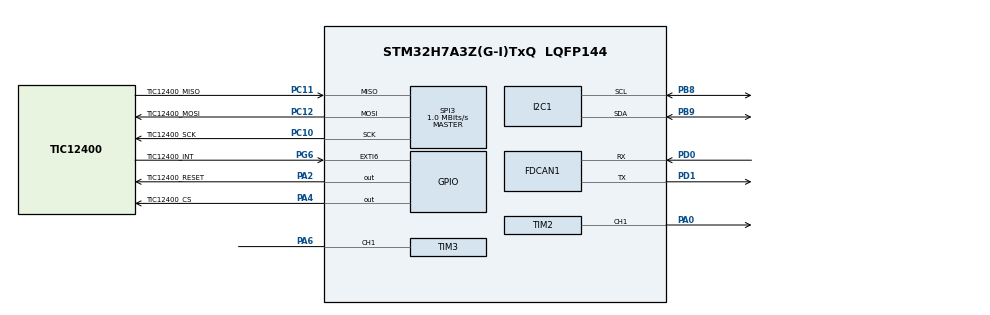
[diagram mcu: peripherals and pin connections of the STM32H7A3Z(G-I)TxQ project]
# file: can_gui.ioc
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CORTEX_M7.default_mode_Activation=1
FDCAN1.AutoRetransmission=ENABLE
FDCAN1.CalculateBaudRateNominal=500000
FDCAN1.CalculateTimeBitNominal=2000
FDCAN1.CalculateTimeQuantumNominal=125.0
FDCAN1.ExtFiltersNbr=1
FDCAN1.NominalPrescaler=4
FDCAN1.NominalSyncJumpWidth=4
FDCAN1.NominalTimeSeg1=12
FDCAN1.NominalTimeSeg2=3
FDCAN1.RxFifo0ElmtsNbr=32
FDCAN1.StdFiltersNbr=1
FDCAN1.TxFifoQueueElmtsNbr=3
IWDG1.Prescaler=IWDG_PRESCALER_128
IWDG1.Reload=999
IWDG1.Window=4095
Mcu.Family=STM32H7
Mcu.Name=STM32H7A3Z(G-I)TxQ
Mcu.Package=LQFP144
NUCLEO-H7A3ZI-Q.BUTTON=1
NUCLEO-H7A3ZI-Q.LD1=true
NUCLEO-H7A3ZI-Q.LD2=true
NUCLEO-H7A3ZI-Q.LD3=true
NUCLEO-H7A3ZI-Q.VCP=true
NVIC.EXTI15_10_IRQn=true\:15\:0\:false\:false\:true\:false\:true\:true
NVIC.EXTI9_5_IRQn=true\:3\:0\:false\:false\:true\:true\:true\:true
NVIC.FDCAN1_IT0_IRQn=true\:2\:0\:false\:false\:true\:true\:true\:true
NVIC.PriorityGroup=NVIC_PRIORITYGROUP_4
PA0.Signal=S_TIM2_CH1_ETR
PA2.GPIO_Label=TIC12400_RESET
PA2.GPIO_ModeDefaultOutputPP=GPIO_MODE_OUTPUT_PP
PA2.GPIO_PuPd=GPIO_NOPULL
PA2.GPIO_Speed=GPIO_SPEED_FREQ_LOW
PA2.PinState=GPIO_PIN_RESET
PA2.Signal=GPIO_Output
PA4.GPIO_Label=TIC12400_CS
PA4.GPIO_ModeDefaultOutputPP=GPIO_MODE_OUTPUT_PP
PA4.GPIO_PuPd=GPIO_NOPULL
PA4.GPIO_Speed=GPIO_SPEED_FREQ_LOW
PA4.PinState=GPIO_PIN_SET
PA4.Signal=GPIO_Output
PA6.Signal=S_TIM3_CH1
PB8.GPIO_Pu=GPIO_PULLUP
PB8.Mode=I2C
PB8.Signal=I2C1_SCL
PB9.GPIO_Pu=GPIO_PULLUP
PB9.Mode=I2C
PB9.Signal=I2C1_SDA
PC10.GPIO_Label=TIC12400_SCK
PC10.GPIO_Speed=GPIO_SPEED_FREQ_HIGH
PC10.Mode=Full_Duplex_Master
PC10.Signal=SPI3_SCK
PC11.GPIO_Label=TIC12400_MISO
PC11.GPIO_Speed=GPIO_SPEED_FREQ_HIGH
PC11.Mode=Full_Duplex_Master
PC11.Signal=SPI3_MISO
PC12.GPIO_Label=TIC12400_MOSI
PC12.GPIO_Speed=GPIO_SPEED_FREQ_HIGH
PC12.Mode=Full_Duplex_Master
PC12.Signal=SPI3_MOSI
PC14-OSC32_IN.GPIO_Label=OSC32_IN
PC14-OSC32_IN.Signal=RCC_OSC32_IN
PC15-OSC32_OUT.GPIO_Label=OSC32_OUT
PC15-OSC32_OUT.Signal=RCC_OSC32_OUT
PD0.Mode=FDCAN_Activate
PD0.Signal=FDCAN1_RX
PD1.Mode=FDCAN_Activate
PD1.Signal=FDCAN1_TX
PD8.Signal=USART3_TX
PD9.Signal=USART3_RX
PG6.GPIO_Label=TIC12400_INT
PG6.GPIO_ModeDefaultEXTI=GPIO_MODE_IT_FALLING
PG6.GPIO_PuPd=GPIO_NOPULL
PG6.Signal=GPXTI6
PH0-OSC_IN.GPIO_Label=PH0-MCU
PH0-OSC_IN.Signal=RCC_OSC_IN
PH1-OSC_OUT.GPIO_Label=PH1-MCU
PH1-OSC_OUT.Signal=RCC_OSC_OUT
ProjectManager.HeapSize=0x200
ProjectManager.StackSize=0x800
ProjectManager.TargetToolchain=STM32CubeIDE
RCC.ADCFreq_Value=129000000
RCC.APB1Freq_Value=64000000
RCC.APB2Freq_Value=64000000
RCC.APB3Freq_Value=64000000
RCC.APB4Freq_Value=64000000
RCC.CortexFreq_Value=64000000
RCC.DIVM1=3
RCC.DIVM3=1
RCC.DIVN1=96
RCC.DIVP1=4
RCC.DIVN3=24
RCC.DIVQ1=8
RCC.DIVR1=4
RCC.HCLKFreq_Value=64000000
RCC.HSE_VALUE=8000000
RCC.PLLFRACN=0
RCC.PLLSourceVirtual=RCC_PLLSOURCE_HSE
RCC.PWR_Regulator_Voltage_Scale=PWR_REGULATOR_VOLTAGE_SCALE0
RCC.SYSCLKFreq_VALUE=64000000
RCC.SYSCLKSource=RCC_SYSCLKSOURCE_PLLCLK
RCC.SupplySource=PWR_DIRECT_SMPS_SUPPLY
RCC.USBCLockSelection=RCC_USBCLKSOURCE_HSI48
RCC.USBFreq_Value=48000000
SH.S_TIM2_CH1_ETR.0=TIM2_CH1,PWM Generation1 CH1
SH.S_TIM3_CH1.0=TIM3_CH1,PWM Input on CH1
SPI3.BaudRatePrescaler=SPI_BAUDRATEPRESCALER_32
SPI3.CLKPhase=SPI_PHASE_2EDGE
SPI3.CLKPolarity=SPI_POLARITY_LOW
SPI3.CRCCalculation=SPI_CRCCALCULATION_DISABLE
SPI3.CalculateBaudRate=1.0 MBits/s
SPI3.DataSize=SPI_DATASIZE_8BIT
SPI3.Direction=SPI_DIRECTION_2LINES
SPI3.FirstBit=SPI_FIRSTBIT_MSB
SPI3.MasterKeepIOState=SPI_MASTER_KEEP_IO_STATE_ENABLE
SPI3.Mode=SPI_MODE_MASTER
SPI3.NSSPMode=SPI_NSS_PULSE_DISABLE
SPI3.VirtualNSS=VM_NSSSOFT
SPI3.VirtualType=VM_MASTER
TIM2.AutoReloadPreload=TIM_AUTORELOAD_PRELOAD_ENABLE
TIM2.Channel-PWM\ Generation1\ CH1=TIM_CHANNEL_1
TIM2.Period=999
TIM2.Prescaler=63
TIM2.Pulse-PWM\ Generation1\ CH1=500
TIM3.Channel-PWM\ Input\ on\ CH1=TIM_CHANNEL_1
TIM3.Period=65535
TIM3.Prescaler=63
VP_IWDG1_VS_IWDG.Mode=IWDG_Activate
VP_MEMORYMAP_VS_MEMORYMAP.Mode=CurAppReg
VP_NUCLEO-H7A3ZI-Q_VS_BSP_COMMON.Mode=COMMON
VP_TIM2_VS_ClockSourceINT.Mode=Internal
VP_TIM3_VS_ClockSourceINT.Mode=Internal
board=NUCLEO-H7A3ZI-Q

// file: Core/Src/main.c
/* USER CODE BEGIN Header */
/**
  ******************************************************************************
  * @file           : main.c
  * @brief          : Main program body
  ******************************************************************************
  * @attention
  *
  * Copyright (c) 2026 STMicroelectronics.
  * All rights reserved.
  *
  * This software is licensed under terms that can be found in the LICENSE file
  * in the root directory of this software component.
  * If no LICENSE file comes with this software, it is provided AS-IS.
  *
  ******************************************************************************
  */
/* USER CODE END Header */
#include "main.h"

/* USER CODE BEGIN Includes */
#include "can_app.h"
#include "app_control.h"
#include "app_fault.h"
#include "app_irq_policy.h"
#include "app_safe_state.h"
#include "app_startup.h"
#include "app_timing.h"
#include "rtc_app.h"
#include "app_log.h"
#include "app_reset_reason.h"
#include "app_watchdog.h"
#include "app_watchdog_evidence.h"
#include "pwm_control.h"
#include "input_capture.h"
#include "pwm_self_test.h"
#include "tic12400_probe.h"
#include "tic12400_can.h"

/* USER CODE END Includes */

/* USER CODE BEGIN PD */
#define APP_PLL_M                         3UL
#define APP_PLL_N                         96UL
#define APP_PLL_P                         4UL
#define APP_PLL_Q                         8UL
#define APP_PLL_R                         4UL
#define APP_FDCAN_NOMINAL_PRESCALER       4UL
#define APP_FDCAN_NOMINAL_TIME_SEG1       12UL
#define APP_FDCAN_NOMINAL_TIME_SEG2       3UL
#define APP_FDCAN_NOMINAL_TQ_COUNT        \
  (1UL + APP_FDCAN_NOMINAL_TIME_SEG1 + APP_FDCAN_NOMINAL_TIME_SEG2)
#define APP_PLL_VCO_HZ                    \
  ((HSE_VALUE * APP_PLL_N) / APP_PLL_M)
#define APP_SYSCLK_HZ                     (APP_PLL_VCO_HZ / APP_PLL_P)
#define APP_FDCAN_KERNEL_CLOCK_HZ         (APP_PLL_VCO_HZ / APP_PLL_Q)
#define APP_FDCAN_NOMINAL_BITRATE_HZ      \
  (APP_FDCAN_KERNEL_CLOCK_HZ / APP_FDCAN_NOMINAL_PRESCALER / \
   APP_FDCAN_NOMINAL_TQ_COUNT)
#define APP_FDCAN_MESSAGE_RAM_WORDS        \
  (1UL + 2UL + (CAN_APP_RX_FIFO0_ELEMENTS * 4UL) + (3UL * 4UL))

_Static_assert(HSE_VALUE == 8000000UL,
               "Board clock tree requires the 8 MHz ST-LINK MCO");
_Static_assert(APP_PLL_VCO_HZ == 256000000UL,
               "PLL VCO clock changed");
_Static_assert(APP_SYSCLK_HZ == 64000000UL,
               "System clock changed");
_Static_assert(APP_FDCAN_KERNEL_CLOCK_HZ == 32000000UL,
               "FDCAN kernel clock changed");
_Static_assert(APP_FDCAN_NOMINAL_BITRATE_HZ == 500000UL,
               "FDCAN nominal bitrate changed");
_Static_assert(CAN_APP_RX_FIFO0_ELEMENTS <= 64U,
               "FDCAN RX FIFO0 exceeds the hardware limit");
_Static_assert(CAN_APP_RX_FIFO0_WATERMARK < CAN_APP_RX_FIFO0_ELEMENTS,
               "FDCAN RX FIFO0 watermark must leave burst headroom");
_Static_assert(APP_FDCAN_MESSAGE_RAM_WORDS <= 2560UL,
               "FDCAN message RAM allocation exceeds SRAMCAN");
_Static_assert(__NVIC_PRIO_BITS == 4U,
               "IRQ policy requires 16 Cortex-M7 priority levels");
_Static_assert(TICK_INT_PRIORITY == APP_IRQ_PRIORITY_SYSTICK,
               "HAL tick priority diverges from the IRQ policy");
_Static_assert(BSP_BUTTON_USER_IT_PRIORITY ==
               APP_IRQ_PRIORITY_USER_BUTTON,
               "BSP button priority diverges from the IRQ policy");
/* USER CODE END PD */

COM_InitTypeDef BspCOMInit;

FDCAN_HandleTypeDef hfdcan1;

I2C_HandleTypeDef hi2c1;

IWDG_HandleTypeDef hiwdg1;

SPI_HandleTypeDef hspi3;

TIM_HandleTypeDef htim2;
TIM_HandleTypeDef htim3;

/* USER CODE BEGIN PV */
volatile uint8_t g_fdcan1_msp_ready;
volatile uint8_t g_i2c1_msp_ready;
volatile uint8_t g_spi3_msp_ready;
/* USER CODE END PV */

void SystemClock_Config(void);
static void MPU_Config(void);
static void MX_GPIO_Init(void);
static App_Startup_Result_t MX_FDCAN1_Init(void);
static App_Startup_Result_t MX_I2C1_Init(void);
static App_Startup_Result_t MX_SPI3_Init(void);
static void MX_IWDG1_Init(void);
static App_Startup_Result_t MX_TIM2_Init(void);
static App_Startup_Result_t MX_TIM3_Init(void);

int main(void)
{

  /* USER CODE BEGIN 1 */
  App_Startup_Result_t init_result;
  uint32_t loop_timing_start;
  uint32_t service_timing_start;

  /* USER CODE END 1 */

  /* MPU Configuration--------------------------------------------------------*/
  MPU_Config();

  /* MCU Configuration--------------------------------------------------------*/

  /* Reset of all peripherals, Initializes the Flash interface and the Systick. */
  HAL_Init();

  /* USER CODE BEGIN Init */

  App_ResetReason_Capture();
  App_Fault_CaptureBoot();
  App_Watchdog_Evidence_CaptureBoot(App_ResetReason_WasIwdgReset());

  /* USER CODE END Init */

  /* Configure the system clock */
  SystemClock_Config();

  /* USER CODE BEGIN SysInit */

  App_Timing_Init(SystemCoreClock);

  /* USER CODE END SysInit */

  /* Initialize all configured peripherals */
  MX_GPIO_Init();
  App_SafeState_Engage();
  App_Startup_Init(APP_STARTUP_EXPECTED_RESOURCES);

  /* IWDG is mandatory and starts before non-critical peripherals. */
  MX_IWDG1_Init();
  if (App_Watchdog_Init(&hiwdg1) != HAL_OK)
  {
    Error_Handler();
  }

  init_result = MX_FDCAN1_Init();
  App_Startup_Record(APP_STARTUP_RESOURCE_FDCAN, init_result);
  init_result = MX_I2C1_Init();
  App_Startup_Record(APP_STARTUP_RESOURCE_I2C, init_result);
  init_result = MX_SPI3_Init();
  App_Startup_Record(APP_STARTUP_RESOURCE_SPI, init_result);
  init_result = MX_TIM2_Init();
  App_Startup_Record(APP_STARTUP_RESOURCE_PWM_TIMER, init_result);
  if (init_result != APP_STARTUP_RESULT_OK)
  {
    App_SafeState_Engage();
  }
  init_result = MX_TIM3_Init();
  App_Startup_Record(APP_STARTUP_RESOURCE_CAPTURE_TIMER, init_result);
  /* USER CODE BEGIN 2 */
  App_Log_Init();
  App_Fault_Snapshot_t fault_snapshot;
  App_Fault_GetSnapshot(&fault_snapshot);
  if (fault_snapshot.valid != 0U)
  {
    (void)App_Log_Push(APP_LOG_SOURCE_SYSTEM,
                       APP_LOG_SEVERITY_FAULT,
                       APP_LOG_EVENT_CPU_FAULT,
                       fault_snapshot.type,
                       fault_snapshot.pc);
    (void)App_Log_Push(APP_LOG_SOURCE_SYSTEM,
                       APP_LOG_SEVERITY_FAULT,
                       APP_LOG_EVENT_CPU_FAULT_STATUS,
                       fault_snapshot.cfsr,
                       fault_snapshot.hfsr);
  }
  if (App_Startup_IsReady(APP_STARTUP_RESOURCE_PWM_TIMER) != 0U)
  {
    init_result =
        (PWM_Control_Init(&htim2,
                          TIM_CHANNEL_1,
                          1000000UL) == PWM_CONTROL_OK)
        ? APP_STARTUP_RESULT_OK
        : APP_STARTUP_RESULT_PWM_CONTROL_INIT;
  }
  else
  {
    init_result = APP_STARTUP_RESULT_PWM_CONTROL_INIT;
  }
  App_Startup_Record(APP_STARTUP_RESOURCE_PWM_CONTROL, init_result);

  if ((init_result == APP_STARTUP_RESULT_OK) &&
      (PWM_Control_Set(10000U, 90U) != PWM_CONTROL_OK))
  {
    init_result = APP_STARTUP_RESULT_PWM_CONTROL_DEFAULT;
    App_Startup_Record(APP_STARTUP_RESOURCE_PWM_CONTROL, init_result);
    App_SafeState_Engage();
  }

  if (App_Startup_IsReady(APP_STARTUP_RESOURCE_CAPTURE_TIMER) != 0U)
  {
    init_result =
        (Input_Capture_Init(&htim3, 1000000UL) == INPUT_CAPTURE_OK)
        ? APP_STARTUP_RESULT_OK
        : APP_STARTUP_RESULT_INPUT_CAPTURE_INIT;
  }
  else
  {
    init_result = APP_STARTUP_RESULT_INPUT_CAPTURE_INIT;
  }
  App_Startup_Record(APP_STARTUP_RESOURCE_INPUT_CAPTURE, init_result);

  TIC12400_Probe_Init(
      &hspi3,
      App_Startup_IsReady(APP_STARTUP_RESOURCE_SPI));
  PWM_SelfTest_Init();
  App_Control_Init();
  App_ResetReason_Snapshot_t reset_reason;
  App_ResetReason_GetSnapshot(&reset_reason);
  (void)App_Log_Push(APP_LOG_SOURCE_SYSTEM,
                     APP_LOG_SEVERITY_INFO,
                     APP_LOG_EVENT_SYSTEM_BOOT,
                     reset_reason.decoded_flags,
                     reset_reason.raw_rsr);

  App_Watchdog_ResetEvidence_t watchdog_evidence;
  App_Watchdog_Evidence_Get(&watchdog_evidence);
  if (watchdog_evidence.valid != 0U)
  {
    (void)App_Log_Push(APP_LOG_SOURCE_SYSTEM,
                       APP_LOG_SEVERITY_FAULT,
                       APP_LOG_EVENT_WATCHDOG_RESET_EVIDENCE,
                       watchdog_evidence.cause,
                       watchdog_evidence.missing_heartbeat_mask);
  }

  (void)CAN_App_Init(
      App_Startup_IsReady(APP_STARTUP_RESOURCE_FDCAN));
  TIC12400_CAN_Init();
  PCA2131_Init_Check(
      App_Startup_IsReady(APP_STARTUP_RESOURCE_I2C));
  if (CAN_App_IsAvailable() != 0U)
  {
    CAN_Send_System_Status();
  }

  /* USER CODE END 2 */

  /* Initialize leds */
  BSP_LED_Init(LED_GREEN);
  BSP_LED_Init(LED_YELLOW);
  BSP_LED_Init(LED_RED);
  if (CAN_App_IsAvailable() == 0U)
  {
    BSP_LED_On(LED_YELLOW);
  }

  /* Initialize USER push-button, will be used to trigger an interrupt each time it's pressed.*/
  BSP_PB_Init(BUTTON_USER, BUTTON_MODE_EXTI);

  /* Initialize COM1 port (115200, 8 bits (7-bit data + 1 stop bit), no parity */
  BspCOMInit.BaudRate   = 115200;
  BspCOMInit.WordLength = COM_WORDLENGTH_8B;
  BspCOMInit.StopBits   = COM_STOPBITS_1;
  BspCOMInit.Parity     = COM_PARITY_NONE;
  BspCOMInit.HwFlowCtl  = COM_HWCONTROL_NONE;
  if (BSP_COM_Init(COM1, &BspCOMInit) != BSP_ERROR_NONE)
  {
    App_Startup_Record(APP_STARTUP_RESOURCE_COM,
                       APP_STARTUP_RESULT_COM_INIT);
  }
  else
  {
    App_Startup_Record(APP_STARTUP_RESOURCE_COM,
                       APP_STARTUP_RESULT_OK);
  }

  App_Startup_Snapshot_t startup_snapshot;
  App_Startup_GetSnapshot(&startup_snapshot);
  if (startup_snapshot.degraded != 0U)
  {
    BSP_LED_On(LED_YELLOW);
    (void)App_Log_Push(APP_LOG_SOURCE_SYSTEM,
                       APP_LOG_SEVERITY_FAULT,
                       APP_LOG_EVENT_STARTUP_DEGRADED,
                       startup_snapshot.failed_mask,
                       startup_snapshot.first_failure_result);
  }

  /* Infinite loop */
  /* USER CODE BEGIN WHILE */
  while (1)
  {

    loop_timing_start = App_Timing_Begin();

    /* USER CODE END WHILE */

    /* USER CODE BEGIN 3 */

	  service_timing_start = App_Timing_Begin();
	  TIC12400_Probe_Process();
	  App_Timing_End(APP_TIMING_SERVICE_TIC12400_PROBE,
	                 service_timing_start);

	  service_timing_start = App_Timing_Begin();
	  App_Control_Process();
	  App_Timing_End(APP_TIMING_SERVICE_CONTROL, service_timing_start);

	  service_timing_start = App_Timing_Begin();
	  RTC_Process();
	  App_Watchdog_CheckIn(APP_WATCHDOG_HEARTBEAT_RTC_SERVICE);
	  App_Timing_End(APP_TIMING_SERVICE_RTC, service_timing_start);

	  service_timing_start = App_Timing_Begin();
	  Input_Capture_Process();
	  App_Timing_End(APP_TIMING_SERVICE_INPUT_CAPTURE,
	                 service_timing_start);

	  service_timing_start = App_Timing_Begin();
	  CAN_App_Process();
	  App_Timing_End(APP_TIMING_SERVICE_CAN_APP, service_timing_start);

	  service_timing_start = App_Timing_Begin();
	  TIC12400_CAN_Process();
	  App_Timing_End(APP_TIMING_SERVICE_TIC12400_CAN,
	                 service_timing_start);

	  service_timing_start = App_Timing_Begin();
	  App_Watchdog_CheckIn(APP_WATCHDOG_HEARTBEAT_MAIN_LOOP);
	  App_Watchdog_Process();
	  App_Timing_End(APP_TIMING_SERVICE_WATCHDOG,
	                 service_timing_start);

	  App_Timing_End(APP_TIMING_SERVICE_MAIN_LOOP, loop_timing_start);

  }
  /* USER CODE END 3 */
}

void SystemClock_Config(void)
{
  RCC_OscInitTypeDef RCC_OscInitStruct = {0};
  RCC_ClkInitTypeDef RCC_ClkInitStruct = {0};

  /*AXI clock gating */
  RCC->CKGAENR = 0xE003FFFF;

  /** Supply configuration update enable
  */
  HAL_PWREx_ConfigSupply(PWR_DIRECT_SMPS_SUPPLY);

  /** Configure the main internal regulator output voltage
  */
  __HAL_PWR_VOLTAGESCALING_CONFIG(PWR_REGULATOR_VOLTAGE_SCALE0);

  while(!__HAL_PWR_GET_FLAG(PWR_FLAG_VOSRDY)) {}

  /** Initializes the RCC Oscillators according to the specified parameters
  * in the RCC_OscInitTypeDef structure.
  */
  RCC_OscInitStruct.OscillatorType = RCC_OSCILLATORTYPE_HSE
                                   | RCC_OSCILLATORTYPE_HSI
                                   | RCC_OSCILLATORTYPE_LSI;
  RCC_OscInitStruct.HSEState = RCC_HSE_BYPASS;
  RCC_OscInitStruct.HSIState = RCC_HSI_DIV1;
  RCC_OscInitStruct.HSICalibrationValue = 64;
  RCC_OscInitStruct.LSIState = RCC_LSI_ON;
  RCC_OscInitStruct.PLL.PLLState = RCC_PLL_ON;
  RCC_OscInitStruct.PLL.PLLSource = RCC_PLLSOURCE_HSE;
  RCC_OscInitStruct.PLL.PLLM = APP_PLL_M;
  RCC_OscInitStruct.PLL.PLLN = APP_PLL_N;
  RCC_OscInitStruct.PLL.PLLP = APP_PLL_P;
  RCC_OscInitStruct.PLL.PLLQ = APP_PLL_Q;
  RCC_OscInitStruct.PLL.PLLR = APP_PLL_R;
  RCC_OscInitStruct.PLL.PLLRGE = RCC_PLL1VCIRANGE_1;
  RCC_OscInitStruct.PLL.PLLVCOSEL = RCC_PLL1VCOWIDE;
  RCC_OscInitStruct.PLL.PLLFRACN = 0;
  if (HAL_RCC_OscConfig(&RCC_OscInitStruct) != HAL_OK)
  {
    Error_Handler();
  }

  /** Initializes the CPU, AHB and APB buses clocks
  */
  RCC_ClkInitStruct.ClockType = RCC_CLOCKTYPE_HCLK|RCC_CLOCKTYPE_SYSCLK
                              |RCC_CLOCKTYPE_PCLK1|RCC_CLOCKTYPE_PCLK2
                              |RCC_CLOCKTYPE_D3PCLK1|RCC_CLOCKTYPE_D1PCLK1;
  RCC_ClkInitStruct.SYSCLKSource = RCC_SYSCLKSOURCE_PLLCLK;
  RCC_ClkInitStruct.SYSCLKDivider = RCC_SYSCLK_DIV1;
  RCC_ClkInitStruct.AHBCLKDivider = RCC_HCLK_DIV1;
  RCC_ClkInitStruct.APB3CLKDivider = RCC_APB3_DIV1;
  RCC_ClkInitStruct.APB1CLKDivider = RCC_APB1_DIV1;
  RCC_ClkInitStruct.APB2CLKDivider = RCC_APB2_DIV1;
  RCC_ClkInitStruct.APB4CLKDivider = RCC_APB4_DIV1;

  if (HAL_RCC_ClockConfig(&RCC_ClkInitStruct, FLASH_LATENCY_1) != HAL_OK)
  {
    Error_Handler();
  }
}

static App_Startup_Result_t MX_FDCAN1_Init(void)
{
  HAL_StatusTypeDef hal_status;

  hfdcan1.Instance = FDCAN1;
  hfdcan1.Init.FrameFormat = FDCAN_FRAME_CLASSIC;
  hfdcan1.Init.Mode = FDCAN_MODE_NORMAL;
  hfdcan1.Init.AutoRetransmission = ENABLE;
  hfdcan1.Init.TransmitPause = DISABLE;
  hfdcan1.Init.ProtocolException = DISABLE;
  hfdcan1.Init.NominalPrescaler = APP_FDCAN_NOMINAL_PRESCALER;
  hfdcan1.Init.NominalSyncJumpWidth = 4;
  hfdcan1.Init.NominalTimeSeg1 = APP_FDCAN_NOMINAL_TIME_SEG1;
  hfdcan1.Init.NominalTimeSeg2 = APP_FDCAN_NOMINAL_TIME_SEG2;
  hfdcan1.Init.DataPrescaler = 1;
  hfdcan1.Init.DataSyncJumpWidth = 1;
  hfdcan1.Init.DataTimeSeg1 = 1;
  hfdcan1.Init.DataTimeSeg2 = 1;
  hfdcan1.Init.MessageRAMOffset = 0;
  hfdcan1.Init.StdFiltersNbr = 1;
  hfdcan1.Init.ExtFiltersNbr = 1;
  hfdcan1.Init.RxFifo0ElmtsNbr = CAN_APP_RX_FIFO0_ELEMENTS;
  hfdcan1.Init.RxFifo0ElmtSize = FDCAN_DATA_BYTES_8;
  hfdcan1.Init.RxFifo1ElmtsNbr = 0;
  hfdcan1.Init.RxFifo1ElmtSize = FDCAN_DATA_BYTES_8;
  hfdcan1.Init.RxBuffersNbr = 0;
  hfdcan1.Init.RxBufferSize = FDCAN_DATA_BYTES_8;
  hfdcan1.Init.TxEventsNbr = 0;
  hfdcan1.Init.TxBuffersNbr = 0;
  hfdcan1.Init.TxFifoQueueElmtsNbr = 3;
  hfdcan1.Init.TxFifoQueueMode = FDCAN_TX_FIFO_OPERATION;
  hfdcan1.Init.TxElmtSize = FDCAN_DATA_BYTES_8;
  g_fdcan1_msp_ready = 0U;
  hal_status = HAL_FDCAN_Init(&hfdcan1);
  if (g_fdcan1_msp_ready == 0U)
  {
    return APP_STARTUP_RESULT_FDCAN_MSP_CLOCK;
  }
  if (hal_status != HAL_OK)
  {
    return APP_STARTUP_RESULT_FDCAN_HAL_INIT;
  }

  return APP_STARTUP_RESULT_OK;
}

static App_Startup_Result_t MX_I2C1_Init(void)
{
  HAL_StatusTypeDef hal_status;

  hi2c1.Instance = I2C1;
  hi2c1.Init.Timing = 0x10707DBC;
  hi2c1.Init.OwnAddress1 = 0;
  hi2c1.Init.AddressingMode = I2C_ADDRESSINGMODE_7BIT;
  hi2c1.Init.DualAddressMode = I2C_DUALADDRESS_DISABLE;
  hi2c1.Init.OwnAddress2 = 0;
  hi2c1.Init.OwnAddress2Masks = I2C_OA2_NOMASK;
  hi2c1.Init.GeneralCallMode = I2C_GENERALCALL_DISABLE;
  hi2c1.Init.NoStretchMode = I2C_NOSTRETCH_DISABLE;
  g_i2c1_msp_ready = 0U;
  hal_status = HAL_I2C_Init(&hi2c1);
  if (g_i2c1_msp_ready == 0U)
  {
    return APP_STARTUP_RESULT_I2C_MSP_CLOCK;
  }
  if (hal_status != HAL_OK)
  {
    return APP_STARTUP_RESULT_I2C_HAL_INIT;
  }

  /** Configure Analogue filter
  */
  if (HAL_I2CEx_ConfigAnalogFilter(&hi2c1, I2C_ANALOGFILTER_ENABLE) != HAL_OK)
  {
    return APP_STARTUP_RESULT_I2C_ANALOG_FILTER;
  }

  /** Configure Digital filter
  */
  if (HAL_I2CEx_ConfigDigitalFilter(&hi2c1, 0) != HAL_OK)
  {
    return APP_STARTUP_RESULT_I2C_DIGITAL_FILTER;
  }

  return APP_STARTUP_RESULT_OK;
}

static App_Startup_Result_t MX_SPI3_Init(void)
{
  HAL_StatusTypeDef hal_status;
  hspi3.Instance = SPI3;
  hspi3.Init.Mode = SPI_MODE_MASTER;
  hspi3.Init.Direction = SPI_DIRECTION_2LINES;
  hspi3.Init.DataSize = SPI_DATASIZE_8BIT;
  hspi3.Init.CLKPolarity = SPI_POLARITY_LOW;
  hspi3.Init.CLKPhase = SPI_PHASE_2EDGE;
  hspi3.Init.NSS = SPI_NSS_SOFT;
  hspi3.Init.BaudRatePrescaler = SPI_BAUDRATEPRESCALER_32;
  hspi3.Init.FirstBit = SPI_FIRSTBIT_MSB;
  hspi3.Init.TIMode = SPI_TIMODE_DISABLE;
  hspi3.Init.CRCCalculation = SPI_CRCCALCULATION_DISABLE;
  hspi3.Init.CRCPolynomial = 0x7U;
  hspi3.Init.CRCLength = SPI_CRC_LENGTH_DATASIZE;
  hspi3.Init.NSSPMode = SPI_NSS_PULSE_DISABLE;
  hspi3.Init.NSSPolarity = SPI_NSS_POLARITY_LOW;
  hspi3.Init.FifoThreshold = SPI_FIFO_THRESHOLD_01DATA;
  hspi3.Init.TxCRCInitializationPattern =
      SPI_CRC_INITIALIZATION_ALL_ZERO_PATTERN;
  hspi3.Init.RxCRCInitializationPattern =
      SPI_CRC_INITIALIZATION_ALL_ZERO_PATTERN;
  hspi3.Init.MasterSSIdleness = SPI_MASTER_SS_IDLENESS_00CYCLE;
  hspi3.Init.MasterInterDataIdleness =
      SPI_MASTER_INTERDATA_IDLENESS_00CYCLE;
  hspi3.Init.MasterReceiverAutoSusp = SPI_MASTER_RX_AUTOSUSP_DISABLE;
  hspi3.Init.MasterKeepIOState = SPI_MASTER_KEEP_IO_STATE_ENABLE;
  hspi3.Init.IOSwap = SPI_IO_SWAP_DISABLE;
  g_spi3_msp_ready = 0U;
  hal_status = HAL_SPI_Init(&hspi3);
  if (g_spi3_msp_ready == 0U)
  {
    return APP_STARTUP_RESULT_SPI_MSP_CLOCK;
  }
  if (hal_status != HAL_OK)
  {
    return APP_STARTUP_RESULT_SPI_HAL_INIT;
  }

  return APP_STARTUP_RESULT_OK;
}

static void MX_IWDG1_Init(void)
{

  hiwdg1.Instance = IWDG1;
  hiwdg1.Init.Prescaler = IWDG_PRESCALER_128;
  hiwdg1.Init.Window = 4095;
  hiwdg1.Init.Reload = 999;
  if (HAL_IWDG_Init(&hiwdg1) != HAL_OK)
  {
    Error_Handler();
  }

}

static App_Startup_Result_t MX_TIM2_Init(void)
{

  TIM_ClockConfigTypeDef sClockSourceConfig = {0};
  TIM_MasterConfigTypeDef sMasterConfig = {0};
  TIM_OC_InitTypeDef sConfigOC = {0};

  htim2.Instance = TIM2;
  htim2.Init.Prescaler = 63;
  htim2.Init.CounterMode = TIM_COUNTERMODE_UP;
  htim2.Init.Period = 999;
  htim2.Init.ClockDivision = TIM_CLOCKDIVISION_DIV1;
  htim2.Init.AutoReloadPreload = TIM_AUTORELOAD_PRELOAD_ENABLE;
  if (HAL_TIM_Base_Init(&htim2) != HAL_OK)
  {
    return APP_STARTUP_RESULT_PWM_TIMER_BASE;
  }
  sClockSourceConfig.ClockSource = TIM_CLOCKSOURCE_INTERNAL;
  if (HAL_TIM_ConfigClockSource(&htim2, &sClockSourceConfig) != HAL_OK)
  {
    return APP_STARTUP_RESULT_PWM_TIMER_CLOCK;
  }
  if (HAL_TIM_PWM_Init(&htim2) != HAL_OK)
  {
    return APP_STARTUP_RESULT_PWM_TIMER_PWM;
  }
  sMasterConfig.MasterOutputTrigger = TIM_TRGO_RESET;
  sMasterConfig.MasterSlaveMode = TIM_MASTERSLAVEMODE_DISABLE;
  if (HAL_TIMEx_MasterConfigSynchronization(&htim2, &sMasterConfig) != HAL_OK)
  {
    return APP_STARTUP_RESULT_PWM_TIMER_MASTER;
  }
  sConfigOC.OCMode = TIM_OCMODE_PWM1;
  sConfigOC.Pulse = 500;
  sConfigOC.OCPolarity = TIM_OCPOLARITY_HIGH;
  sConfigOC.OCFastMode = TIM_OCFAST_DISABLE;
  if (HAL_TIM_PWM_ConfigChannel(&htim2, &sConfigOC, TIM_CHANNEL_1) != HAL_OK)
  {
    return APP_STARTUP_RESULT_PWM_TIMER_CHANNEL;
  }
  HAL_TIM_MspPostInit(&htim2);

  return APP_STARTUP_RESULT_OK;
}

/**
  * @brief TIM3 PWM input initialization (PA6, CH1 period / CH2 pulse)
  */
static App_Startup_Result_t MX_TIM3_Init(void)
{
  TIM_IC_InitTypeDef sConfigIC = {0};
  TIM_SlaveConfigTypeDef sSlaveConfig = {0};
  TIM_MasterConfigTypeDef sMasterConfig = {0};

  htim3.Instance = TIM3;
  htim3.Init.Prescaler = 63;
  htim3.Init.CounterMode = TIM_COUNTERMODE_UP;
  htim3.Init.Period = 65535;
  htim3.Init.ClockDivision = TIM_CLOCKDIVISION_DIV1;
  htim3.Init.AutoReloadPreload = TIM_AUTORELOAD_PRELOAD_DISABLE;
  if (HAL_TIM_IC_Init(&htim3) != HAL_OK)
  {
    return APP_STARTUP_RESULT_CAPTURE_TIMER_INIT;
  }

  sSlaveConfig.SlaveMode = TIM_SLAVEMODE_RESET;
  sSlaveConfig.InputTrigger = TIM_TS_TI1FP1;
  sSlaveConfig.TriggerPolarity = TIM_INPUTCHANNELPOLARITY_RISING;
  sSlaveConfig.TriggerPrescaler = TIM_ICPSC_DIV1;
  sSlaveConfig.TriggerFilter = 0;
  if (HAL_TIM_SlaveConfigSynchro(&htim3, &sSlaveConfig) != HAL_OK)
  {
    return APP_STARTUP_RESULT_CAPTURE_TIMER_SLAVE;
  }

  sConfigIC.ICPolarity = TIM_INPUTCHANNELPOLARITY_RISING;
  sConfigIC.ICSelection = TIM_ICSELECTION_DIRECTTI;
  sConfigIC.ICPrescaler = TIM_ICPSC_DIV1;
  sConfigIC.ICFilter = 0;
  if (HAL_TIM_IC_ConfigChannel(&htim3, &sConfigIC, TIM_CHANNEL_1) != HAL_OK)
  {
    return APP_STARTUP_RESULT_CAPTURE_TIMER_CHANNEL_1;
  }

  sConfigIC.ICPolarity = TIM_INPUTCHANNELPOLARITY_FALLING;
  sConfigIC.ICSelection = TIM_ICSELECTION_INDIRECTTI;
  if (HAL_TIM_IC_ConfigChannel(&htim3, &sConfigIC, TIM_CHANNEL_2) != HAL_OK)
  {
    return APP_STARTUP_RESULT_CAPTURE_TIMER_CHANNEL_2;
  }

  sMasterConfig.MasterOutputTrigger = TIM_TRGO_RESET;
  sMasterConfig.MasterSlaveMode = TIM_MASTERSLAVEMODE_DISABLE;
  if (HAL_TIMEx_MasterConfigSynchronization(&htim3, &sMasterConfig) != HAL_OK)
  {
    return APP_STARTUP_RESULT_CAPTURE_TIMER_MASTER;
  }

  return APP_STARTUP_RESULT_OK;
}

static void MX_GPIO_Init(void)
{
  GPIO_InitTypeDef GPIO_InitStruct = {0};

  /* GPIO Ports Clock Enable */
  __HAL_RCC_GPIOC_CLK_ENABLE();
  __HAL_RCC_GPIOH_CLK_ENABLE();
  __HAL_RCC_GPIOA_CLK_ENABLE();
  __HAL_RCC_GPIOD_CLK_ENABLE();
  __HAL_RCC_GPIOB_CLK_ENABLE();
  __HAL_RCC_GPIOG_CLK_ENABLE();

  /* Safe inactive levels before enabling the output drivers. */
  HAL_GPIO_WritePin(TIC12400_CS_GPIO_Port,
                    TIC12400_CS_Pin,
                    GPIO_PIN_SET);
  HAL_GPIO_WritePin(TIC12400_RESET_GPIO_Port,
                    TIC12400_RESET_Pin,
                    GPIO_PIN_RESET);

  GPIO_InitStruct.Pin = TIC12400_RESET_Pin | TIC12400_CS_Pin;
  GPIO_InitStruct.Mode = GPIO_MODE_OUTPUT_PP;
  GPIO_InitStruct.Pull = GPIO_NOPULL;
  GPIO_InitStruct.Speed = GPIO_SPEED_FREQ_LOW;
  HAL_GPIO_Init(GPIOA, &GPIO_InitStruct);

  GPIO_InitStruct.Pin = TIC12400_INT_Pin;
  GPIO_InitStruct.Mode = GPIO_MODE_IT_FALLING;
  GPIO_InitStruct.Pull = GPIO_NOPULL;
  HAL_GPIO_Init(TIC12400_INT_GPIO_Port, &GPIO_InitStruct);

  HAL_NVIC_SetPriority(TIC12400_INT_EXTI_IRQn,
                       APP_IRQ_PRIORITY_TIC12400_EXTI,
                       APP_IRQ_SUBPRIORITY);
  HAL_NVIC_EnableIRQ(TIC12400_INT_EXTI_IRQn);

}

 /* MPU Configuration */

void MPU_Config(void)
{
  MPU_Region_InitTypeDef MPU_InitStruct = {0};

  /* Disables the MPU */
  HAL_MPU_Disable();

  /** Initializes and configures the Region and the memory to be protected
  */
  MPU_InitStruct.Enable = MPU_REGION_ENABLE;
  MPU_InitStruct.Number = MPU_REGION_NUMBER0;
  MPU_InitStruct.BaseAddress = 0x0;
  MPU_InitStruct.Size = MPU_REGION_SIZE_4GB;
  MPU_InitStruct.SubRegionDisable = 0x87;
  MPU_InitStruct.TypeExtField = MPU_TEX_LEVEL0;
  MPU_InitStruct.AccessPermission = MPU_REGION_NO_ACCESS;
  MPU_InitStruct.DisableExec = MPU_INSTRUCTION_ACCESS_DISABLE;
  MPU_InitStruct.IsShareable = MPU_ACCESS_SHAREABLE;
  MPU_InitStruct.IsCacheable = MPU_ACCESS_NOT_CACHEABLE;
  MPU_InitStruct.IsBufferable = MPU_ACCESS_NOT_BUFFERABLE;

  HAL_MPU_ConfigRegion(&MPU_InitStruct);
  /* Enables the MPU */
  HAL_MPU_Enable(MPU_PRIVILEGED_DEFAULT);

}

void Error_Handler(void)
{
  /* USER CODE BEGIN Error_Handler_Debug */
  uint32_t return_address =
      (uint32_t)(uintptr_t)__builtin_return_address(0);

  __disable_irq();
  App_SafeState_Engage();
  App_Fault_RecordExceptionFromIsr(APP_FAULT_ERROR_HANDLER,
                                   NULL,
                                   return_address);
  __DSB();
  NVIC_SystemReset();

  while (1)
  {
  }
  /* USER CODE END Error_Handler_Debug */
}
